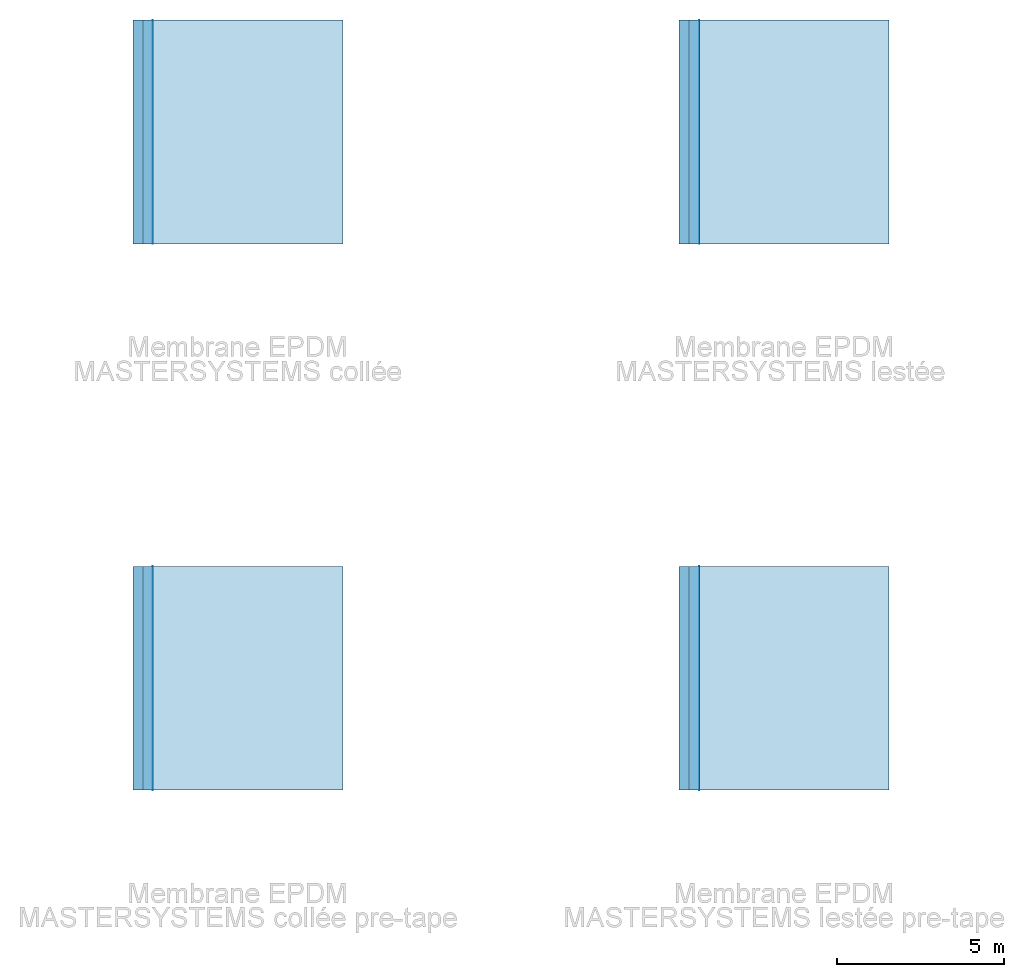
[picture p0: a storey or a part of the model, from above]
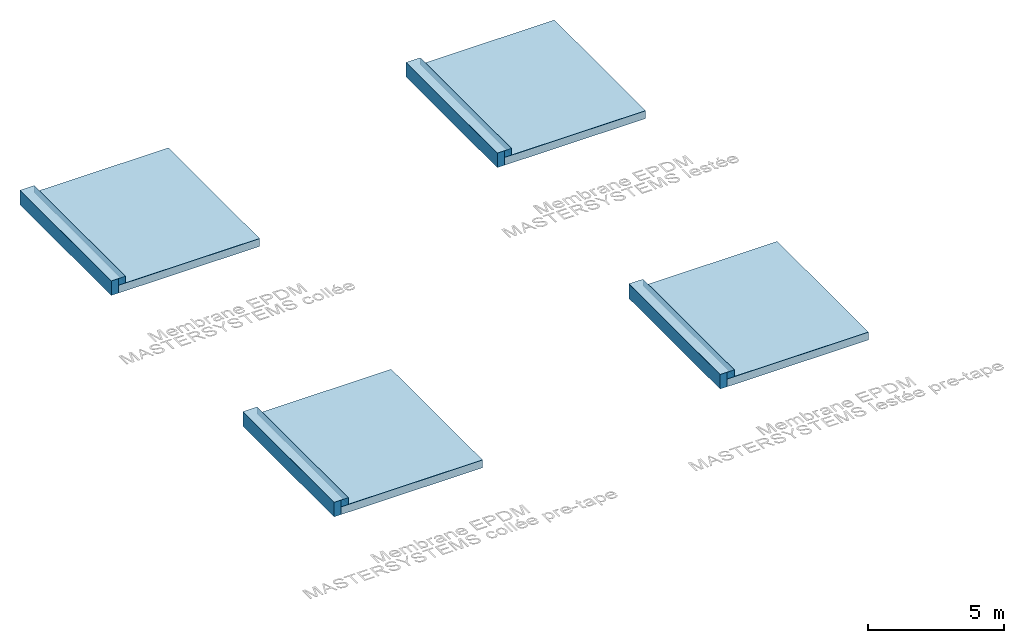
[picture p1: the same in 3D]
Properties of the parts of a building model (IFC2X3)

# File
Description: ViewDefinition [CoordinationView_V2.0]
Time: 2024-08-13T15:47:38
Written by: The EXPRESS Data Manager Version 5.02.0100.07 : 28 Aug 2013
Made in: 22.0.2.392 - Exporter 22.0.2.392 - Interface utilisateur alternative 22.0.2.392
Comment: STEP Physical File produced by: The EXPRESS Data Manager Version 5.02.0100.07 : 28 Aug 2013 * Module: EDMstepFileFactory/EDMstandAlone * Creation date: Tue Aug 13 15:47:38 2024 * Host: VM-BAG-LT-163 * Database: C:\Users\u051572\AppData\Local\Temp\b8f7576d-5c44-48b1-8c19-4d0dc5ed1b91\b6ed495f-eca0-470a-80a5-08c0bd33e367\ifc * Database version: 5507 * Database creation date: Tue Aug 13 15:47:36 2024 * Schema: IFC2X3 * Model: DataRepository.ifc * Model creation date: Tue Aug 13 15:47:37 2024 * Header model: DataRepository.ifc_HeaderModel * Header model creation date: Tue Aug 13 15:47:37 2024 * EDMuser: sdai-user * EDMgroup: sdai-group * License ID and type: 5605 : Permanent license. Expiry date: * EDMstepFileFactory options: 020000

# IfcSite, Default
RefLatitude: 42, 24, 53, 508911; RefLongitude: -71, -15, -29, -58837; RefElevation: 0 mm

# IfcBuilding
Pset_BuildingCommon - NumberOfStoreys: 1

# IfcBuildingStorey: Niveau:Niveau 1, Niveau 1
LongName: Niveau 1; Elevation: 0 mm

# IfcBuildingElementProxy: Texte 3D:Model Text 1 (4)
In: Niveau 1
Pset_BuildingElementProxyCommon - Reference: Model Text 1; sets with these values: 2
Pset_ProvisionForVoid - Shape: Undefined; Width: 10 mm; Depth: 10 mm
Name (Texte 3D:Model Text 1:...) | Height (mm)
38042 | 602.738
40742 | 602.738
40918 | 75.3422
40946 | 75.3422

# IfcRoof: Toit de base:Membrane MASTERSYSTEMS EPDM collée, Toit de base:Membrane MASTERSYSTEMS EPDM collée:43501
In: Niveau 1
Pset_ManufacturerTypeInformation - Manufacturer: https://www.vmbuildingsolutions.com/fr-fr/homepage
Pset_QuantityTakeOff - Reference: Membrane MASTERSYSTEMS EPDM collée
Pset_RoofCommon - IsExternal: yes; Reference: Membrane MASTERSYSTEMS EPDM collée; ProjectedArea: 38.2724 m2; TotalArea: 38.2724 m2

# IfcRoof: Toit de base:Membrane MASTERSYSTEMS EPDM collée Pre-Tape, Toit de base:Membrane MASTERSYSTEMS EPDM collée Pre-Tape:43742
In: Niveau 1
Pset_ManufacturerTypeInformation - Manufacturer: https://www.vmbuildingsolutions.com/fr-fr/homepage
Pset_QuantityTakeOff - Reference: Membrane MASTERSYSTEMS EPDM collée Pre-Tape
Pset_RoofCommon - IsExternal: yes; Reference: Membrane MASTERSYSTEMS EPDM collée Pre-Tape; ProjectedArea: 38.2724 m2; TotalArea: 38.2724 m2

# IfcRoof: Toit de base:Membrane MASTERSYSTEMS EPDM collée-Relevés et acrotères (4)
In: Niveau 1
Pset_ManufacturerTypeInformation - Manufacturer: https://www.vmbuildingsolutions.com/fr-fr/homepage
Pset_QuantityTakeOff - Reference: Membrane MASTERSYSTEMS EPDM collée-Relevés et acrotères
Pset_RoofCommon - IsExternal: yes; Reference: Membrane MASTERSYSTEMS EPDM collée-Relevés et acrotères; ProjectedArea: 4.05083 m2; TotalArea: 4.05083 m2
Name (Toit de base:Membrane MASTERSYSTEMS EPDM collée-Relevés et acrotères:...)
42986
43529
43770
44112

# IfcRoof: Toit de base:Membrane MASTERSYSTEMS EPDM lestée, Toit de base:Membrane MASTERSYSTEMS EPDM lestée:42958
In: Niveau 1
Pset_QuantityTakeOff - Reference: Membrane MASTERSYSTEMS EPDM lestée
Pset_RoofCommon - Reference: Membrane MASTERSYSTEMS EPDM lestée; IsExternal: yes; ProjectedArea: 38.2724 m2; TotalArea: 38.2724 m2

# IfcRoof: Toit de base:Membrane MASTERSYSTEMS EPDM lestée Pre-tape, Toit de base:Membrane MASTERSYSTEMS EPDM lestée Pre-tape:44084
In: Niveau 1
Pset_ManufacturerTypeInformation - Manufacturer: https://www.vmbuildingsolutions.com/fr-fr/homepage
Pset_QuantityTakeOff - Reference: Membrane MASTERSYSTEMS EPDM lestée Pre-tape
Pset_RoofCommon - IsExternal: yes; Reference: Membrane MASTERSYSTEMS EPDM lestée Pre-tape; ProjectedArea: 38.2724 m2; TotalArea: 38.2724 m2

# IfcRoof: Toit de base:Toit 1 (4)
In: Niveau 1
Pset_QuantityTakeOff - Reference: Toit 1
Pset_RoofCommon - IsExternal: yes; Reference: Toit 1; ProjectedArea: 40.2868 m2; TotalArea: 40.2868 m2
Name (Toit de base:Toit 1:...)
42965
43508
43749
44091

# IfcSlab: Toit de base:Membrane MASTERSYSTEMS EPDM collée, Toit de base:Membrane MASTERSYSTEMS EPDM collée:43501
In: Niveau 1
Type - PredefinedType: ROOF
Type - Pset_ManufacturerTypeInformation - Manufacturer: https://www.vmbuildingsolutions.com/fr-fr/homepage
Type - Pset_ReinforcementBarPitchOfSlab - Description: Membrane d’étanchéité EPDM qui dispose d’une sous-couche en polyester. Celle-ci répartit la pression de la vapeur sous toute la nappe. Existe en deux versions: 1-Standard: 3.05mx15.25m Les joints longitudinaux sont réalisés soit au moyen de Masterbond Polyback soit à la colle PX200 ou px300 2-Pre-Tape: 3.05mx15.25m et 1.5mx12.20m Les joints longitudinaux sont réalisés soit au moyen de la bande Pre-tape préfabriquée (pour la version Mastersystems Pre-tape) soit au moyen d’un ruban double face prévulcanisé Masterbond Polyback.
Type - Pset_SlabCommon - IsExternal: yes
Material: Membrane EPDM caoutchouc MASTERSYSTEMS collée 2.2 mm, Colle MASTERCONTACT PX300 1.1 mm
Pset_QuantityTakeOff - Reference: Membrane MASTERSYSTEMS EPDM collée
Pset_ReinforcementBarPitchOfSlab - Reference: Membrane MASTERSYSTEMS EPDM collée
Pset_SlabCommon - PitchAngle: 0 deg; Reference: Membrane MASTERSYSTEMS EPDM collée

# IfcSlab: Toit de base:Membrane MASTERSYSTEMS EPDM collée Pre-Tape, Toit de base:Membrane MASTERSYSTEMS EPDM collée Pre-Tape:43742
In: Niveau 1
Type - PredefinedType: ROOF
Type - Pset_ManufacturerTypeInformation - Manufacturer: https://www.vmbuildingsolutions.com/fr-fr/homepage
Type - Pset_ReinforcementBarPitchOfSlab - Description: Membrane d’étanchéité EPDM qui dispose d’une sous-couche en polyester. Celle-ci répartit la pression de la vapeur sous toute la nappe. Existe en deux versions: 1-Standard: 3.05mx15.25m Les joints longitudinaux sont réalisés soit au moyen de Masterbond Polyback soit à la colle PX200 ou px300 2-Pre-Tape: 3.05mx15.25m et 1.5mx12.20m Les joints longitudinaux sont réalisés soit au moyen de la bande Pre-tape préfabriquée (pour la version Mastersystems Pre-tape) soit au moyen d’un ruban double face prévulcanisé Masterbond Polyback.
Type - Pset_SlabCommon - IsExternal: yes
Material: Membrane EPDM caoutchouc MASTERSYSTEMS collée pre-tape 2.2 mm, Colle MASTERCONTACT PX300 1.1 mm
Pset_QuantityTakeOff - Reference: Membrane MASTERSYSTEMS EPDM collée Pre-Tape
Pset_ReinforcementBarPitchOfSlab - Reference: Membrane MASTERSYSTEMS EPDM collée Pre-Tape
Pset_SlabCommon - PitchAngle: 0 deg; Reference: Membrane MASTERSYSTEMS EPDM collée Pre-Tape

# IfcSlab: Toit de base:Membrane MASTERSYSTEMS EPDM collée-Relevés et acrotères (4)
In: Niveau 1
Type - PredefinedType: ROOF
Type - Pset_ManufacturerTypeInformation - Manufacturer: https://www.vmbuildingsolutions.com/fr-fr/homepage
Type - Pset_ReinforcementBarPitchOfSlab - Description: Membrane d’étanchéité EPDM qui dispose d’une sous-couche en polyester. Celle-ci répartit la pression de la vapeur sous toute la nappe. Existe en deux versions: 1-Standard: 3.05mx15.25m Les joints longitudinaux sont réalisés soit au moyen de Masterbond Polyback soit à la colle PX200 ou px300 2-Pre-Tape: 3.05mx15.25m et 1.5mx12.20m Les joints longitudinaux sont réalisés soit au moyen de la bande Pre-tape préfabriquée (pour la version Mastersystems Pre-tape) soit au moyen d’un ruban double face prévulcanisé Masterbond Polyback.
Type - Pset_SlabCommon - IsExternal: yes
Material: Membrane EPDM caoutchouc MASTERSYSTEMS collée-Relevés et acrotères 2.2 mm, Colle MASTERCONTACT PX300 1.1 mm
Pset_QuantityTakeOff - Reference: Membrane MASTERSYSTEMS EPDM collée-Relevés et acrotères
Pset_ReinforcementBarPitchOfSlab - Reference: Membrane MASTERSYSTEMS EPDM collée-Relevés et acrotères
Pset_SlabCommon - PitchAngle: 0 deg; Reference: Membrane MASTERSYSTEMS EPDM collée-Relevés et acrotères
Name (Toit de base:Membrane MASTERSYSTEMS EPDM collée-Relevés et acrotères:...)
42986
43529
43770
44112

# IfcSlab: Toit de base:Membrane MASTERSYSTEMS EPDM lestée, Toit de base:Membrane MASTERSYSTEMS EPDM lestée:42958
In: Niveau 1
Type - PredefinedType: ROOF
Type - Pset_ReinforcementBarPitchOfSlab - Description: Membrane d’étanchéité EPDM qui dispose d’une sous-couche en polyester. Celle-ci répartit la pression de la vapeur sous toute la nappe. Sur les toitures lestées, la bande centrale sera posée non collée. La méthode de pose avec lestage peut seulement s'appliquer sur des pentes de 10% au maximum. Le lestage peut être réalisé au moyen de gravier ou de végétation. Dans certains cas, il est nécessaire de faire appel au bureau d'étude pour valider cette technique selon la portance du plancher de toiture. Tous les joints doivent etres réalisés au moyen de Masterbond Polyback. Les remontées, les angles, les acrotères, les avaloirs, les ventilations, les cheminées, les zones de turbulences... sont encollées à 100% sur 1 m minimum avec la colle Mastercontact PX300 appliqué sur le support et sur la membrane en plein bain afin d'obtenir une adhérence optimale. Existe en deux versions: 1-Standard: 3.05mx15.25m 2-Pre-Tape: 3.05mx15.25m et 1.5mx12.20m
Type - Pset_SlabCommon - IsExternal: yes
Material: Film de protection polyester 0.8 mm, Membrane EPDM caoutchouc MASTERSYSTEMS lestée 2.2 mm
Pset_QuantityTakeOff - Reference: Membrane MASTERSYSTEMS EPDM lestée
Pset_ReinforcementBarPitchOfSlab - Reference: Membrane MASTERSYSTEMS EPDM lestée
Pset_SlabCommon - Reference: Membrane MASTERSYSTEMS EPDM lestée; PitchAngle: 0 deg

# IfcSlab: Toit de base:Membrane MASTERSYSTEMS EPDM lestée Pre-tape, Toit de base:Membrane MASTERSYSTEMS EPDM lestée Pre-tape:44084
In: Niveau 1
Type - PredefinedType: ROOF
Type - Pset_ManufacturerTypeInformation - Manufacturer: https://www.vmbuildingsolutions.com/fr-fr/homepage
Type - Pset_ReinforcementBarPitchOfSlab - Description: Membrane d’étanchéité EPDM qui dispose d’une sous-couche en polyester. Celle-ci répartit la pression de la vapeur sous toute la nappe. Sur les toitures lestées, la bande centrale sera posée non collée. La méthode de pose avec lestage peut seulement s'appliquer sur des pentes de 10% au maximum. Le lestage peut être réalisé au moyen de gravier ou de végétation. Dans certains cas, il est nécessaire de faire appel au bureau d'étude pour valider cette technique selon la portance du plancher de toiture. Tous les joints doivent etres réalisés au moyen de Masterbond Polyback. Les remontées, les angles, les acrotères, les avaloirs, les ventilations, les cheminées, les zones de turbulences... sont encollées à 100% sur 1 m minimum avec la colle Mastercontact PX300 appliqué sur le support et sur la membrane en plein bain afin d'obtenir une adhérence optimale. Existe en deux versions: 1-Standard: 3.05mx15.25m 2-Pre-Tape: 3.05mx15.25m et 1.5mx12.20m
Type - Pset_SlabCommon - IsExternal: yes
Material: Film de protection polyester 0.8 mm, Membrane EPDM caoutchouc MASTERSYSTEMS lestée pre-tape 2.2 mm
Pset_QuantityTakeOff - Reference: Membrane MASTERSYSTEMS EPDM lestée Pre-tape
Pset_ReinforcementBarPitchOfSlab - Reference: Membrane MASTERSYSTEMS EPDM lestée Pre-tape
Pset_SlabCommon - PitchAngle: 0 deg; Reference: Membrane MASTERSYSTEMS EPDM lestée Pre-tape

# IfcSlab: Toit de base:Toit 1 (4)
In: Niveau 1
Type - PredefinedType: ROOF
Type - Pset_SlabCommon - IsExternal: yes
Material: Isolation 100 mm, Pare vapeur 0.8 mm, Béton de pente 50 mm, Structure porteuse 200 mm
Pset_QuantityTakeOff - Reference: Toit 1; sets with these values: 2
Pset_SlabCommon - PitchAngle: 0 deg; Reference: Toit 1
Name (Toit de base:Toit 1:...)
42965
43508
43749
44091

# IfcWallStandardCase: Mur de base:Membrane MASTERSYSTEMS EPDM collée-Relevés et acrotères (4)
In: Niveau 1
Type - PredefinedType: STANDARD; Material: Membrane EPDM caoutchouc MASTERSYSTEMS collée-Relevés et acrotères 2.2 mm, Colle MASTERCONTACT PX300 1.1 mm
Type - Pset_ManufacturerTypeInformation - Manufacturer: https://www.vmbuildingsolutions.com/fr-fr/homepage
Type - Pset_ReinforcementBarPitchOfWall - Description: Membrane d’étanchéité EPDM disposant d’une sous-couche en polyester.
Type - Pset_WallCommon - IsExternal: yes
Pset_QuantityTakeOff - Reference: Membrane MASTERSYSTEMS EPDM collée-Relevés et acrotères
Pset_ReinforcementBarPitchOfWall - Reference: Membrane MASTERSYSTEMS EPDM collée-Relevés et acrotères
Pset_WallCommon - LoadBearing: no; Reference: Membrane MASTERSYSTEMS EPDM collée-Relevés et acrotères
Name (Mur de base:Membrane MASTERSYSTEMS EPDM collée-Relevés et acrotères:...) | ExtendToStructure
42972 | yes
43515 | no
43756 | no
44098 | no

# IfcWallStandardCase: Mur de base:Mur 1 (8)
In: Niveau 1
Type - PredefinedType: STANDARD; Material: Isolation 100 mm, Maçonnerie ascendante 200 mm
Type - Pset_WallCommon - IsExternal: yes
Pset_QuantityTakeOff - Reference: Mur 1; sets with these values: 2
Pset_WallCommon - Reference: Mur 1; LoadBearing: no
Name (Mur de base:Mur 1:...) | ExtendToStructure
42970 | yes
42971 | yes
43513 | no
43514 | no
43754 | no
43755 | no
44096 | no
44097 | no
